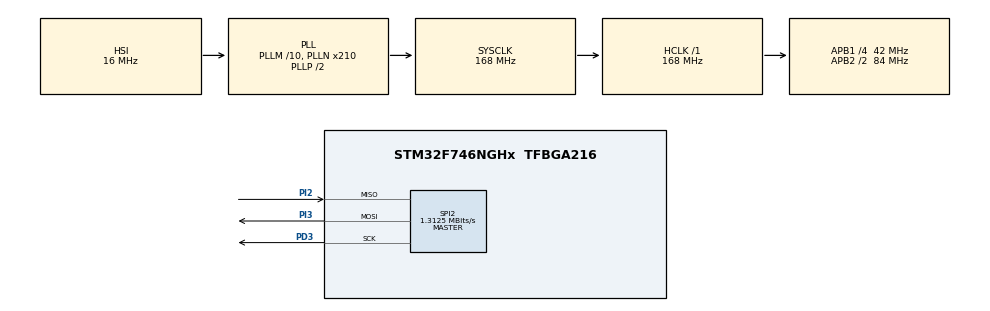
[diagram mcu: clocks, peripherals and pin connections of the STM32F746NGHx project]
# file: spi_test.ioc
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Mcu.Family=STM32F7
Mcu.Name=STM32F746NGHx
Mcu.Package=TFBGA216
NVIC.PriorityGroup=NVIC_PRIORITYGROUP_4
PD3.Mode=Full_Duplex_Master
PD3.Signal=SPI2_SCK
PI2.Mode=Full_Duplex_Master
PI2.Signal=SPI2_MISO
PI3.Mode=Full_Duplex_Master
PI3.Signal=SPI2_MOSI
ProjectManager.HeapSize=0x200
ProjectManager.StackSize=0x400
ProjectManager.TargetToolchain=STM32CubeIDE
RCC.AHBFreq_Value=168000000
RCC.APB1CLKDivider=RCC_HCLK_DIV4
RCC.APB1Freq_Value=42000000
RCC.APB1TimFreq_Value=84000000
RCC.APB2CLKDivider=RCC_HCLK_DIV2
RCC.APB2Freq_Value=84000000
RCC.APB2TimFreq_Value=168000000
RCC.CortexFreq_Value=168000000
RCC.HCLKFreq_Value=168000000
RCC.HSE_VALUE=25000000
RCC.HSI_VALUE=16000000
RCC.LSE_VALUE=32768
RCC.PLLM=10
RCC.PLLN=210
RCC.PLLSourceVirtual=RCC_PLLSOURCE_HSI
RCC.SYSCLKFreq_VALUE=168000000
RCC.SYSCLKSource=RCC_SYSCLKSOURCE_PLLCLK
RCC.USBFreq_Value=168000000
RCC.VCOOutputFreq_Value=336000000
SPI2.BaudRatePrescaler=SPI_BAUDRATEPRESCALER_32
SPI2.CalculateBaudRate=1.3125 MBits/s
SPI2.DataSize=SPI_DATASIZE_8BIT
SPI2.Direction=SPI_DIRECTION_2LINES
SPI2.Mode=SPI_MODE_MASTER
SPI2.NSSPMode=SPI_NSS_PULSE_DISABLE
SPI2.VirtualType=VM_MASTER
board=STM32F746G-DISCO

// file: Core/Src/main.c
/* USER CODE BEGIN Header */
/**
  ******************************************************************************
  * @file           : main.c
  * @brief          : Main program body
  ******************************************************************************
  * @attention
  *
  * Copyright (c) 2025 STMicroelectronics.
  * All rights reserved.
  *
  * This software is licensed under terms that can be found in the LICENSE file
  * in the root directory of this software component.
  * If no LICENSE file comes with this software, it is provided AS-IS.
  *
  ******************************************************************************
  */
/* USER CODE END Header */
#include "main.h"

/* USER CODE BEGIN Includes */
#include "stm32f7xx_hal.h"
#include <stdio.h>
/* USER CODE END Includes */

SPI_HandleTypeDef hspi2;

void SystemClock_Config(void);
void MX_SPI2_Init(void);
void MX_GPIO_Init(void);

void AD7779_WriteRegister(uint8_t reg, uint8_t data);
void AD7779_ReadRegister(uint8_t reg, uint8_t* data);

void AD7779_Reset(void);

int main(void)
{

  /* MCU Configuration--------------------------------------------------------*/

  /* Reset of all peripherals, Initializes the Flash interface and the Systick. */
  HAL_Init();

  /* Configure the system clock */
  SystemClock_Config();

  /* Initialize all configured peripherals */
  MX_GPIO_Init();
  MX_SPI2_Init();
  /* USER CODE BEGIN 2 */
  AD7779_Reset();
  uint8_t chip_id = 0;
      AD7779_ReadRegister(0x07, &chip_id);  // CHIP_ID register

      if (chip_id == 0xAD || chip_id == 0x01)
      {
          printf("AD7779 detected! CHIP_ID = 0x%02X\r\n", chip_id);
      }
      else
      {
          printf("AD7779 not found. Read 0x%02X\r\n", chip_id);
      }
  /* USER CODE END 2 */

  /* Infinite loop */
  while (1)
  {

  }
}

void SystemClock_Config(void)
{
  RCC_OscInitTypeDef RCC_OscInitStruct = {0};
  RCC_ClkInitTypeDef RCC_ClkInitStruct = {0};

  /** Configure the main internal regulator output voltage
  */
  __HAL_RCC_PWR_CLK_ENABLE();
  __HAL_PWR_VOLTAGESCALING_CONFIG(PWR_REGULATOR_VOLTAGE_SCALE2);

  /** Initializes the RCC Oscillators according to the specified parameters
  * in the RCC_OscInitTypeDef structure.
  */
  RCC_OscInitStruct.OscillatorType = RCC_OSCILLATORTYPE_HSI;
  RCC_OscInitStruct.HSIState = RCC_HSI_ON;
  RCC_OscInitStruct.HSICalibrationValue = RCC_HSICALIBRATION_DEFAULT;
  RCC_OscInitStruct.PLL.PLLState = RCC_PLL_ON;
  RCC_OscInitStruct.PLL.PLLSource = RCC_PLLSOURCE_HSI;
  RCC_OscInitStruct.PLL.PLLM = 10;
  RCC_OscInitStruct.PLL.PLLN = 210;
  RCC_OscInitStruct.PLL.PLLP = RCC_PLLP_DIV2;
  RCC_OscInitStruct.PLL.PLLQ = 2;
  if (HAL_RCC_OscConfig(&RCC_OscInitStruct) != HAL_OK)
  {
    Error_Handler();
  }

  /** Initializes the CPU, AHB and APB buses clocks
  */
  RCC_ClkInitStruct.ClockType = RCC_CLOCKTYPE_HCLK|RCC_CLOCKTYPE_SYSCLK
                              |RCC_CLOCKTYPE_PCLK1|RCC_CLOCKTYPE_PCLK2;
  RCC_ClkInitStruct.SYSCLKSource = RCC_SYSCLKSOURCE_PLLCLK;
  RCC_ClkInitStruct.AHBCLKDivider = RCC_SYSCLK_DIV1;
  RCC_ClkInitStruct.APB1CLKDivider = RCC_HCLK_DIV4;
  RCC_ClkInitStruct.APB2CLKDivider = RCC_HCLK_DIV2;

  if (HAL_RCC_ClockConfig(&RCC_ClkInitStruct, FLASH_LATENCY_5) != HAL_OK)
  {
    Error_Handler();
  }
}

void MX_SPI2_Init(void)
{

  /* SPI2 parameter configuration*/
  hspi2.Instance = SPI2;
  hspi2.Init.Mode = SPI_MODE_MASTER;
  hspi2.Init.Direction = SPI_DIRECTION_2LINES;
  hspi2.Init.DataSize = SPI_DATASIZE_8BIT;
  hspi2.Init.CLKPolarity = SPI_POLARITY_LOW;
  hspi2.Init.CLKPhase = SPI_PHASE_1EDGE;
  hspi2.Init.NSS = SPI_NSS_SOFT;
  hspi2.Init.BaudRatePrescaler = SPI_BAUDRATEPRESCALER_32;
  hspi2.Init.FirstBit = SPI_FIRSTBIT_MSB;
  hspi2.Init.TIMode = SPI_TIMODE_DISABLE;
  hspi2.Init.CRCCalculation = SPI_CRCCALCULATION_DISABLE;
  hspi2.Init.CRCPolynomial = 7;
  hspi2.Init.CRCLength = SPI_CRC_LENGTH_DATASIZE;
  hspi2.Init.NSSPMode = SPI_NSS_PULSE_DISABLE;
  if (HAL_SPI_Init(&hspi2) != HAL_OK)
  {
    Error_Handler();
  }

}

void MX_GPIO_Init(void)
{
    GPIO_InitTypeDef GPIO_InitStruct = {0};

    __HAL_RCC_GPIOB_CLK_ENABLE();  // For CS, MISO, MOSI
    __HAL_RCC_GPIOD_CLK_ENABLE();  // For SCLK
    __HAL_RCC_GPIOF_CLK_ENABLE();  // For RESET, START, DRDY1

    // PB12 - CS
    GPIO_InitStruct.Pin = GPIO_PIN_12;
    GPIO_InitStruct.Mode = GPIO_MODE_OUTPUT_PP;
    GPIO_InitStruct.Pull = GPIO_NOPULL;
    GPIO_InitStruct.Speed = GPIO_SPEED_FREQ_HIGH;
    HAL_GPIO_Init(GPIOB, &GPIO_InitStruct);
    HAL_GPIO_WritePin(GPIOB, GPIO_PIN_12, GPIO_PIN_SET);  // CS HIGH

    // PF6 - RESET
    GPIO_InitStruct.Pin = GPIO_PIN_6;
    HAL_GPIO_Init(GPIOF, &GPIO_InitStruct);
    HAL_GPIO_WritePin(GPIOF, GPIO_PIN_6, GPIO_PIN_SET);  // RESET HIGH

    // PF7 - nSTART
    GPIO_InitStruct.Pin = GPIO_PIN_7;
    HAL_GPIO_Init(GPIOF, &GPIO_InitStruct);
    HAL_GPIO_WritePin(GPIOF, GPIO_PIN_7, GPIO_PIN_RESET); // Keep LOW

    // PF9 - DRDY1 (input)
    GPIO_InitStruct.Pin = GPIO_PIN_9;
    GPIO_InitStruct.Mode = GPIO_MODE_INPUT;
    GPIO_InitStruct.Pull = GPIO_NOPULL;
    HAL_GPIO_Init(GPIOF, &GPIO_InitStruct);
}

/* USER CODE BEGIN 4 */
void AD7779_WriteRegister(uint8_t reg, uint8_t data)
{
    uint8_t tx[2];
    tx[0] = 0x00 | (reg & 0x3F);  // Write command
    tx[1] = data;

    HAL_GPIO_WritePin(GPIOB, GPIO_PIN_12, GPIO_PIN_RESET); // CS LOW
    HAL_SPI_Transmit(&hspi2, tx, 2, HAL_MAX_DELAY);
    HAL_GPIO_WritePin(GPIOB, GPIO_PIN_12, GPIO_PIN_SET);   // CS HIGH
}

void AD7779_ReadRegister(uint8_t reg, uint8_t* data)
{
    uint8_t tx = 0x40 | (reg & 0x3F);  // Read command
    uint8_t rx = 0;

    HAL_GPIO_WritePin(GPIOB, GPIO_PIN_12, GPIO_PIN_RESET); // CS LOW
    HAL_SPI_Transmit(&hspi2, &tx, 1, HAL_MAX_DELAY);
    HAL_SPI_Receive(&hspi2, &rx, 1, HAL_MAX_DELAY);
    HAL_GPIO_WritePin(GPIOB, GPIO_PIN_12, GPIO_PIN_SET);   // CS HIGH

    *data = rx;
}
void AD7779_Reset(void)
{
    HAL_GPIO_WritePin(GPIOF, GPIO_PIN_6, GPIO_PIN_RESET);  // RESET LOW
    HAL_Delay(10);  // 10ms
    HAL_GPIO_WritePin(GPIOF, GPIO_PIN_6, GPIO_PIN_SET);    // RESET HIGH
    HAL_Delay(10);  // Wait after reset
}

/* USER CODE END 4 */

void Error_Handler(void)
{
  __disable_irq();
  while (1)
  {
  }
}
